VERSION 5.8 ;
BUSBITCHARS "[]" ;
DIVIDERCHAR "/" ;
UNITS
    DATABASE MICRONS 1000 ;
END UNITS

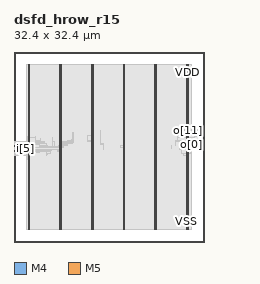
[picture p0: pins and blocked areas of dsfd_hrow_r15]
MACRO dsfd_hrow_r15
  FOREIGN dsfd_hrow_r15 0 0 ;
  CLASS BLOCK ;
  SIZE 32.4 BY 32.4 ;
  PIN ck
    DIRECTION INPUT ;
    USE SIGNAL ;
    PORT
      LAYER M4 ;
        RECT  0 15.408 0.084 15.432 ;
    END
  END ck
  PIN i[0]
    DIRECTION INPUT ;
    USE SIGNAL ;
    PORT
      LAYER M4 ;
        RECT  0 15.504 0.084 15.528 ;
    END
  END i[0]
  PIN i[10]
    DIRECTION INPUT ;
    USE SIGNAL ;
    PORT
      LAYER M4 ;
        RECT  0 16.464 0.084 16.488 ;
    END
  END i[10]
  PIN i[11]
    DIRECTION INPUT ;
    USE SIGNAL ;
    PORT
      LAYER M4 ;
        RECT  0 16.56 0.084 16.584 ;
    END
  END i[11]
  PIN i[12]
    DIRECTION INPUT ;
    USE SIGNAL ;
    PORT
      LAYER M4 ;
        RECT  0 16.656 0.084 16.68 ;
    END
  END i[12]
  PIN i[13]
    DIRECTION INPUT ;
    USE SIGNAL ;
    PORT
      LAYER M4 ;
        RECT  0 16.752 0.084 16.776 ;
    END
  END i[13]
  PIN i[14]
    DIRECTION INPUT ;
    USE SIGNAL ;
    PORT
      LAYER M4 ;
        RECT  0 16.848 0.084 16.872 ;
    END
  END i[14]
  PIN i[1]
    DIRECTION INPUT ;
    USE SIGNAL ;
    PORT
      LAYER M4 ;
        RECT  0 15.6 0.084 15.624 ;
    END
  END i[1]
  PIN i[2]
    DIRECTION INPUT ;
    USE SIGNAL ;
    PORT
      LAYER M4 ;
        RECT  0 15.696 0.084 15.72 ;
    END
  END i[2]
  PIN i[3]
    DIRECTION INPUT ;
    USE SIGNAL ;
    PORT
      LAYER M4 ;
        RECT  0 15.792 0.084 15.816 ;
    END
  END i[3]
  PIN i[4]
    DIRECTION INPUT ;
    USE SIGNAL ;
    PORT
      LAYER M4 ;
        RECT  0 15.888 0.084 15.912 ;
    END
  END i[4]
  PIN i[5]
    DIRECTION INPUT ;
    USE SIGNAL ;
    PORT
      LAYER M4 ;
        RECT  0 15.984 0.084 16.008 ;
    END
  END i[5]
  PIN i[6]
    DIRECTION INPUT ;
    USE SIGNAL ;
    PORT
      LAYER M4 ;
        RECT  0 16.08 0.084 16.104 ;
    END
  END i[6]
  PIN i[7]
    DIRECTION INPUT ;
    USE SIGNAL ;
    PORT
      LAYER M4 ;
        RECT  0 16.176 0.084 16.2 ;
    END
  END i[7]
  PIN i[8]
    DIRECTION INPUT ;
    USE SIGNAL ;
    PORT
      LAYER M4 ;
        RECT  0 16.272 0.084 16.296 ;
    END
  END i[8]
  PIN i[9]
    DIRECTION INPUT ;
    USE SIGNAL ;
    PORT
      LAYER M4 ;
        RECT  0 16.368 0.084 16.392 ;
    END
  END i[9]
  PIN o[0]
    DIRECTION OUTPUT ;
    USE SIGNAL ;
    PORT
      LAYER M4 ;
        RECT  32.316 16.56 32.4 16.584 ;
    END
  END o[0]
  PIN o[10]
    DIRECTION OUTPUT ;
    USE SIGNAL ;
    PORT
      LAYER M4 ;
        RECT  32.316 17.52 32.4 17.544 ;
    END
  END o[10]
  PIN o[11]
    DIRECTION OUTPUT ;
    USE SIGNAL ;
    PORT
      LAYER M4 ;
        RECT  32.316 17.616 32.4 17.64 ;
    END
  END o[11]
  PIN o[12]
    DIRECTION OUTPUT ;
    USE SIGNAL ;
    PORT
      LAYER M4 ;
        RECT  32.316 17.712 32.4 17.736 ;
    END
  END o[12]
  PIN o[13]
    DIRECTION OUTPUT ;
    USE SIGNAL ;
    PORT
      LAYER M4 ;
        RECT  32.316 17.808 32.4 17.832 ;
    END
  END o[13]
  PIN o[14]
    DIRECTION OUTPUT ;
    USE SIGNAL ;
    PORT
      LAYER M4 ;
        RECT  32.316 17.904 32.4 17.928 ;
    END
  END o[14]
  PIN o[1]
    DIRECTION OUTPUT ;
    USE SIGNAL ;
    PORT
      LAYER M4 ;
        RECT  32.316 16.656 32.4 16.68 ;
    END
  END o[1]
  PIN o[2]
    DIRECTION OUTPUT ;
    USE SIGNAL ;
    PORT
      LAYER M4 ;
        RECT  32.316 16.752 32.4 16.776 ;
    END
  END o[2]
  PIN o[3]
    DIRECTION OUTPUT ;
    USE SIGNAL ;
    PORT
      LAYER M4 ;
        RECT  32.316 16.848 32.4 16.872 ;
    END
  END o[3]
  PIN o[4]
    DIRECTION OUTPUT ;
    USE SIGNAL ;
    PORT
      LAYER M4 ;
        RECT  32.316 16.944 32.4 16.968 ;
    END
  END o[4]
  PIN o[5]
    DIRECTION OUTPUT ;
    USE SIGNAL ;
    PORT
      LAYER M4 ;
        RECT  32.316 17.04 32.4 17.064 ;
    END
  END o[5]
  PIN o[6]
    DIRECTION OUTPUT ;
    USE SIGNAL ;
    PORT
      LAYER M4 ;
        RECT  32.316 17.136 32.4 17.16 ;
    END
  END o[6]
  PIN o[7]
    DIRECTION OUTPUT ;
    USE SIGNAL ;
    PORT
      LAYER M4 ;
        RECT  32.316 17.232 32.4 17.256 ;
    END
  END o[7]
  PIN o[8]
    DIRECTION OUTPUT ;
    USE SIGNAL ;
    PORT
      LAYER M4 ;
        RECT  32.316 17.328 32.4 17.352 ;
    END
  END o[8]
  PIN o[9]
    DIRECTION OUTPUT ;
    USE SIGNAL ;
    PORT
      LAYER M4 ;
        RECT  32.316 17.424 32.4 17.448 ;
    END
  END o[9]
  PIN rn
    DIRECTION INPUT ;
    USE SIGNAL ;
    PORT
      LAYER M4 ;
        RECT  0 16.944 0.084 16.968 ;
    END
  END rn
  PIN VDD
    DIRECTION INOUT ;
    USE POWER ;
    PORT
      LAYER M5 ;
        RECT  29.592 2.151 29.712 30.249 ;
        RECT  24.192 2.151 24.312 30.249 ;
        RECT  18.792 2.151 18.912 30.249 ;
        RECT  13.392 2.151 13.512 30.249 ;
        RECT  7.992 2.151 8.112 30.249 ;
        RECT  2.592 2.151 2.712 30.249 ;
    END
  END VDD
  PIN VSS
    DIRECTION INOUT ;
    USE GROUND ;
    PORT
      LAYER M5 ;
        RECT  29.4 2.137 29.52 30.263 ;
        RECT  24 2.137 24.12 30.263 ;
        RECT  18.6 2.137 18.72 30.263 ;
        RECT  13.2 2.137 13.32 30.263 ;
        RECT  7.8 2.137 7.92 30.263 ;
        RECT  2.4 2.137 2.52 30.263 ;
    END
  END VSS
  # OT_OBS_CLOSED layer=M5 d_um=1.536 added=0
  OBS
    LAYER RVTN ;
     RECT  2.16 2.16 30.24 2.295 ;
     RECT  2.16 2.565 30.24 2.835 ;
     RECT  2.16 3.105 30.24 3.375 ;
     RECT  2.16 3.645 30.24 3.915 ;
     RECT  2.16 4.185 30.24 4.455 ;
     RECT  2.16 4.725 30.24 4.995 ;
     RECT  2.16 5.265 30.24 5.535 ;
     RECT  2.16 5.805 30.24 6.075 ;
     RECT  2.16 6.345 30.24 6.615 ;
     RECT  2.16 6.885 30.24 7.155 ;
     RECT  2.16 7.425 30.24 7.695 ;
     RECT  2.16 7.965 30.24 8.235 ;
     RECT  2.16 8.505 30.24 8.775 ;
     RECT  2.16 9.045 30.24 9.315 ;
     RECT  2.16 9.585 30.24 9.855 ;
     RECT  2.16 10.125 30.24 10.395 ;
     RECT  2.16 10.665 30.24 10.935 ;
     RECT  2.16 11.205 30.24 11.475 ;
     RECT  2.16 11.745 30.24 12.015 ;
     RECT  2.16 12.285 30.24 12.555 ;
     RECT  2.16 12.825 30.24 13.095 ;
     RECT  2.16 13.365 30.24 13.635 ;
     RECT  2.16 13.905 30.24 14.175 ;
     RECT  2.16 14.445 30.24 14.715 ;
     RECT  2.16 14.985 30.24 15.255 ;
     RECT  2.16 15.525 30.24 15.795 ;
     RECT  2.16 16.065 30.24 16.335 ;
     RECT  2.16 16.605 30.24 16.875 ;
     RECT  2.16 17.145 30.24 17.415 ;
     RECT  2.16 17.685 30.24 17.955 ;
     RECT  2.16 18.225 30.24 18.495 ;
     RECT  2.16 18.765 30.24 19.035 ;
     RECT  2.16 19.305 30.24 19.575 ;
     RECT  2.16 19.845 30.24 20.115 ;
     RECT  2.16 20.385 30.24 20.655 ;
     RECT  2.16 20.925 30.24 21.195 ;
     RECT  2.16 21.465 30.24 21.735 ;
     RECT  2.16 22.005 30.24 22.275 ;
     RECT  2.16 22.545 30.24 22.815 ;
     RECT  2.16 23.085 30.24 23.355 ;
     RECT  2.16 23.625 30.24 23.895 ;
     RECT  2.16 24.165 30.24 24.435 ;
     RECT  2.16 24.705 30.24 24.975 ;
     RECT  2.16 25.245 30.24 25.515 ;
     RECT  2.16 25.785 30.24 26.055 ;
     RECT  2.16 26.325 30.24 26.595 ;
     RECT  2.16 26.865 30.24 27.135 ;
     RECT  2.16 27.405 30.24 27.675 ;
     RECT  2.16 27.945 30.24 28.215 ;
     RECT  2.16 28.485 30.24 28.755 ;
     RECT  2.16 29.025 30.24 29.295 ;
     RECT  2.16 29.565 30.24 29.835 ;
     RECT  2.16 30.105 30.24 30.24 ;
    LAYER RVTP ;
     RECT  2.16 2.295 30.24 2.565 ;
     RECT  2.16 2.835 30.24 3.105 ;
     RECT  2.16 3.375 30.24 3.645 ;
     RECT  2.16 3.915 30.24 4.185 ;
     RECT  2.16 4.455 30.24 4.725 ;
     RECT  2.16 4.995 30.24 5.265 ;
     RECT  2.16 5.535 30.24 5.805 ;
     RECT  2.16 6.075 30.24 6.345 ;
     RECT  2.16 6.615 30.24 6.885 ;
     RECT  2.16 7.155 30.24 7.425 ;
     RECT  2.16 7.695 30.24 7.965 ;
     RECT  2.16 8.235 30.24 8.505 ;
     RECT  2.16 8.775 30.24 9.045 ;
     RECT  2.16 9.315 30.24 9.585 ;
     RECT  2.16 9.855 30.24 10.125 ;
     RECT  2.16 10.395 30.24 10.665 ;
     RECT  2.16 10.935 30.24 11.205 ;
     RECT  2.16 11.475 30.24 11.745 ;
     RECT  2.16 12.015 30.24 12.285 ;
     RECT  2.16 12.555 30.24 12.825 ;
     RECT  2.16 13.095 30.24 13.365 ;
     RECT  2.16 13.635 30.24 13.905 ;
     RECT  2.16 14.175 30.24 14.445 ;
     RECT  2.16 14.715 30.24 14.985 ;
     RECT  2.16 15.255 30.24 15.525 ;
     RECT  2.16 15.795 30.24 16.065 ;
     RECT  2.16 16.335 30.24 16.605 ;
     RECT  2.16 16.875 30.24 17.145 ;
     RECT  2.16 17.415 30.24 17.685 ;
     RECT  2.16 17.955 30.24 18.225 ;
     RECT  2.16 18.495 30.24 18.765 ;
     RECT  2.16 19.035 30.24 19.305 ;
     RECT  2.16 19.575 30.24 19.845 ;
     RECT  2.16 20.115 30.24 20.385 ;
     RECT  2.16 20.655 30.24 20.925 ;
     RECT  2.16 21.195 30.24 21.465 ;
     RECT  2.16 21.735 30.24 22.005 ;
     RECT  2.16 22.275 30.24 22.545 ;
     RECT  2.16 22.815 30.24 23.085 ;
     RECT  2.16 23.355 30.24 23.625 ;
     RECT  2.16 23.895 30.24 24.165 ;
     RECT  2.16 24.435 30.24 24.705 ;
     RECT  2.16 24.975 30.24 25.245 ;
     RECT  2.16 25.515 30.24 25.785 ;
     RECT  2.16 26.055 30.24 26.325 ;
     RECT  2.16 26.595 30.24 26.865 ;
     RECT  2.16 27.135 30.24 27.405 ;
     RECT  2.16 27.675 30.24 27.945 ;
     RECT  2.16 28.215 30.24 28.485 ;
     RECT  2.16 28.755 30.24 29.025 ;
     RECT  2.16 29.295 30.24 29.565 ;
     RECT  2.16 29.835 30.24 30.105 ;
    LAYER M1 ;
     RECT  2.16 2.151 30.24 30.249 ;
    LAYER M2 ;
     RECT  0.103 14.76 0.139 14.778 ;
     RECT  0.139 14.76 0.175 15.048 ;
     RECT  0.103 16.11 0.239 16.128 ;
     RECT  0.175 14.76 2.16 15.318 ;
     RECT  2.16 2.151 30.24 30.249 ;
     RECT  30.24 18.936 30.731 19.494 ;
     RECT  30.731 18.936 30.767 19.224 ;
     RECT  30.24 16.344 30.803 17.874 ;
     RECT  30.803 17.496 31.307 17.874 ;
     RECT  30.767 19.206 31.307 19.224 ;
     RECT  31.307 17.586 31.343 17.874 ;
     RECT  30.803 16.344 31.379 16.524 ;
     RECT  31.379 16.344 31.415 16.362 ;
    LAYER M3 ;
     RECT  2.415 2.143 2.505 2.413 ;
     RECT  7.815 2.143 7.905 2.413 ;
     RECT  13.215 2.143 13.305 2.413 ;
     RECT  18.615 2.143 18.705 2.413 ;
     RECT  24.015 2.143 24.105 2.413 ;
     RECT  29.415 2.143 29.505 2.413 ;
     RECT  2.415 2.413 2.697 14.071 ;
     RECT  2.304 14.071 2.697 14.369 ;
     RECT  7.815 2.413 8.097 14.611 ;
     RECT  29.415 2.413 29.697 14.791 ;
     RECT  5.472 14.791 5.49 14.989 ;
     RECT  0.108 14.755 0.126 15.025 ;
     RECT  28.908 14.791 29.697 15.025 ;
     RECT  2.376 14.369 2.697 15.061 ;
     RECT  5.472 14.989 5.706 15.061 ;
     RECT  28.908 15.025 29.898 15.061 ;
     RECT  2.376 15.061 2.862 15.151 ;
     RECT  0.108 15.025 0.162 15.223 ;
     RECT  0.108 15.223 0.234 15.259 ;
     RECT  3.816 15.259 3.834 15.331 ;
     RECT  3.816 15.331 4.41 15.421 ;
     RECT  5.472 15.061 6.21 15.421 ;
     RECT  7.776 14.611 8.097 15.421 ;
     RECT  2.376 15.151 3.042 15.457 ;
     RECT  3.816 15.421 6.21 15.457 ;
     RECT  2.376 15.457 6.21 15.529 ;
     RECT  2.34 15.529 6.21 15.565 ;
     RECT  7.488 15.421 8.097 15.565 ;
     RECT  2.34 15.565 6.39 15.691 ;
     RECT  2.304 15.691 6.39 15.727 ;
     RECT  7.416 15.565 8.097 15.727 ;
     RECT  28.584 15.061 30.114 15.835 ;
     RECT  28.26 15.835 30.114 15.989 ;
     RECT  2.304 15.727 8.097 16.105 ;
     RECT  26.784 15.961 26.802 16.105 ;
     RECT  18.615 2.413 18.897 16.141 ;
     RECT  26.784 16.105 26.874 16.169 ;
     RECT  0.108 15.259 0.558 16.205 ;
     RECT  2.304 16.105 8.406 16.259 ;
     RECT  0.108 16.205 0.234 16.349 ;
     RECT  26.856 16.169 26.874 16.403 ;
     RECT  7.668 16.259 8.406 16.411 ;
     RECT  28.62 15.989 30.114 16.411 ;
     RECT  31.392 16.339 31.41 16.411 ;
     RECT  2.304 16.259 5.742 16.445 ;
     RECT  7.668 16.411 8.91 16.501 ;
     RECT  2.304 16.445 5.67 16.529 ;
     RECT  7.668 16.501 9.09 16.529 ;
     RECT  18.18 16.141 18.897 16.529 ;
     RECT  15.192 15.727 15.21 16.645 ;
     RECT  7.815 16.529 9.09 16.681 ;
     RECT  2.304 16.529 5.562 16.747 ;
     RECT  7.815 16.681 9.162 16.771 ;
     RECT  2.268 16.747 5.562 16.799 ;
     RECT  14.724 16.645 15.21 16.799 ;
     RECT  7.815 16.771 9.594 16.879 ;
     RECT  28.62 16.411 31.41 16.951 ;
     RECT  2.268 16.799 5.238 16.973 ;
     RECT  28.332 16.951 31.41 16.973 ;
     RECT  7.815 16.879 9.954 17.041 ;
     RECT  6.48 16.259 6.93 17.069 ;
     RECT  2.304 16.973 5.238 17.105 ;
     RECT  6.48 17.069 6.858 17.105 ;
     RECT  13.215 2.413 13.497 17.113 ;
     RECT  0.108 16.349 0.126 17.117 ;
     RECT  7.815 17.041 10.062 17.141 ;
     RECT  27.504 16.411 27.522 17.185 ;
     RECT  28.332 16.973 31.338 17.185 ;
     RECT  12.528 17.113 13.497 17.221 ;
     RECT  9.144 17.141 10.062 17.249 ;
     RECT  2.34 17.105 4.554 17.339 ;
     RECT  12.456 17.221 13.497 17.339 ;
     RECT  27.504 17.185 31.338 17.339 ;
     RECT  9.792 17.249 10.062 17.519 ;
     RECT  14.724 16.799 14.742 17.581 ;
     RECT  4.536 17.339 4.554 17.609 ;
     RECT  14.724 17.581 14.814 17.609 ;
     RECT  2.34 17.339 3.654 17.645 ;
     RECT  2.376 17.645 3.654 17.879 ;
     RECT  6.48 17.105 6.498 17.879 ;
     RECT  27.864 17.339 31.338 17.879 ;
     RECT  2.376 17.879 2.697 17.951 ;
     RECT  3.636 17.879 3.654 17.951 ;
     RECT  7.815 17.141 8.097 18.031 ;
     RECT  12.528 17.339 13.497 18.149 ;
     RECT  27.864 17.879 31.302 18.185 ;
     RECT  26.784 18.121 26.802 18.221 ;
     RECT  10.044 17.519 10.062 18.599 ;
     RECT  28.044 18.185 31.302 18.599 ;
     RECT  7.815 18.031 8.154 18.833 ;
     RECT  14.796 17.609 14.814 18.841 ;
     RECT  14.724 18.841 14.814 18.959 ;
     RECT  28.044 18.599 29.862 18.959 ;
     RECT  30.708 18.599 31.302 19.229 ;
     RECT  28.584 18.959 29.862 19.265 ;
     RECT  30.708 19.229 30.726 19.499 ;
     RECT  29.052 19.265 29.862 19.571 ;
     RECT  29.124 19.571 29.862 19.805 ;
     RECT  29.34 19.805 29.862 20.039 ;
     RECT  2.415 17.951 2.697 29.987 ;
     RECT  7.815 18.833 8.097 29.987 ;
     RECT  13.215 18.149 13.497 29.987 ;
     RECT  18.615 16.529 18.897 29.987 ;
     RECT  24.015 2.413 24.297 29.987 ;
     RECT  29.415 20.039 29.697 29.987 ;
     RECT  2.415 29.987 2.505 30.257 ;
     RECT  7.815 29.987 7.905 30.257 ;
     RECT  13.215 29.987 13.305 30.257 ;
     RECT  18.615 29.987 18.705 30.257 ;
     RECT  24.015 29.987 24.105 30.257 ;
     RECT  29.415 29.987 29.505 30.257 ;
    LAYER M4 ;
     RECT  0.06 15.408 0.097 16.968 ;
     RECT  0.097 15.408 0.323 17.112 ;
     RECT  0.323 15.504 2.408 17.112 ;
     RECT  2.408 2.148 2.512 30.252 ;
     RECT  2.512 2.418 2.704 29.982 ;
     RECT  2.704 15.552 3.107 16.584 ;
     RECT  2.704 17.664 3.443 17.832 ;
     RECT  3.443 17.808 3.635 17.832 ;
     RECT  3.107 16.08 4.277 16.584 ;
     RECT  4.277 16.08 4.421 16.44 ;
     RECT  4.421 16.416 5.753 16.44 ;
     RECT  7.808 2.148 7.912 30.252 ;
     RECT  7.912 2.418 8.104 29.982 ;
     RECT  13.208 2.148 13.312 30.252 ;
     RECT  13.312 2.418 13.504 29.982 ;
     RECT  18.608 2.148 18.712 30.252 ;
     RECT  18.712 2.418 18.904 29.982 ;
     RECT  24.008 2.148 24.112 30.252 ;
     RECT  24.112 2.418 24.304 29.982 ;
     RECT  29.408 2.148 29.512 30.252 ;
     RECT  29.512 2.418 29.704 29.982 ;
     RECT  29.704 16.56 30.697 17.352 ;
     RECT  30.697 16.56 32.364 17.928 ;
    LAYER M5 ;
     RECT  2.4 2.137 2.52 2.151 ;
     RECT  7.8 2.137 7.92 2.151 ;
     RECT  13.2 2.137 13.32 2.151 ;
     RECT  18.6 2.137 18.72 2.151 ;
     RECT  24 2.137 24.12 2.151 ;
     RECT  29.4 2.137 29.52 2.151 ;
     RECT  2.4 2.151 2.712 15.541 ;
     RECT  0.288 15.397 0.312 16.115 ;
     RECT  2.4 15.541 3.096 16.405 ;
     RECT  2.4 16.405 3.432 16.549 ;
     RECT  2.4 16.549 3.624 17.843 ;
     RECT  2.4 17.843 2.712 30.249 ;
     RECT  7.8 2.151 8.112 30.249 ;
     RECT  13.2 2.151 13.512 30.249 ;
     RECT  18.6 2.151 18.912 30.249 ;
     RECT  24 2.151 24.312 30.249 ;
     RECT  29.4 2.151 29.712 30.249 ;
     RECT  2.4 30.249 2.52 30.263 ;
     RECT  7.8 30.249 7.92 30.263 ;
     RECT  13.2 30.249 13.32 30.263 ;
     RECT  18.6 30.249 18.72 30.263 ;
     RECT  24 30.249 24.12 30.263 ;
     RECT  29.4 30.249 29.52 30.263 ;
  END
END dsfd_hrow_r15
END LIBRARY
